VERSION 5.7 ;
BUSBITCHARS "[]" ;
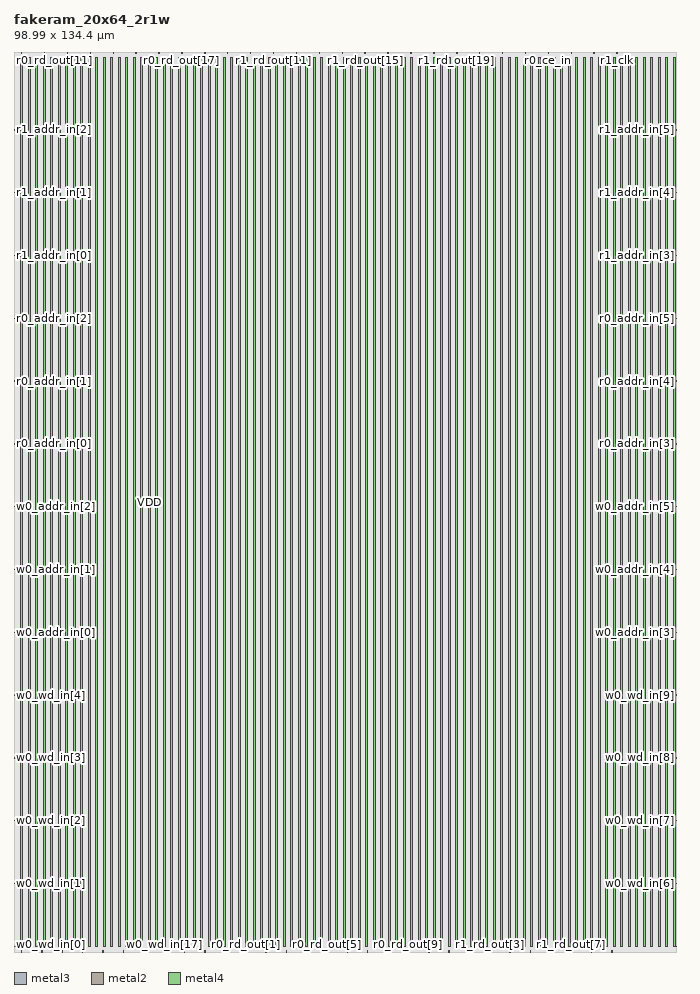
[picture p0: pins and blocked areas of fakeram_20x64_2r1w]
MACRO fakeram_20x64_2r1w
  FOREIGN fakeram_20x64_2r1w 0 0 ;
  SYMMETRY X Y R90 ;
  SIZE 98.990 BY 134.400 ;
  CLASS BLOCK ;
  PIN w0_wd_in[0]
    DIRECTION INPUT ;
    USE SIGNAL ;
    SHAPE ABUTMENT ;
    PORT
      LAYER metal3 ;
      RECT 0.000 0.805 0.210 0.875 ;
    END
  END w0_wd_in[0]
  PIN w0_wd_in[1]
    DIRECTION INPUT ;
    USE SIGNAL ;
    SHAPE ABUTMENT ;
    PORT
      LAYER metal3 ;
      RECT 0.000 10.185 0.210 10.255 ;
    END
  END w0_wd_in[1]
  PIN w0_wd_in[2]
    DIRECTION INPUT ;
    USE SIGNAL ;
    SHAPE ABUTMENT ;
    PORT
      LAYER metal3 ;
      RECT 0.000 19.565 0.210 19.635 ;
    END
  END w0_wd_in[2]
  PIN w0_wd_in[3]
    DIRECTION INPUT ;
    USE SIGNAL ;
    SHAPE ABUTMENT ;
    PORT
      LAYER metal3 ;
      RECT 0.000 28.945 0.210 29.015 ;
    END
  END w0_wd_in[3]
  PIN w0_wd_in[4]
    DIRECTION INPUT ;
    USE SIGNAL ;
    SHAPE ABUTMENT ;
    PORT
      LAYER metal3 ;
      RECT 0.000 38.325 0.210 38.395 ;
    END
  END w0_wd_in[4]
  PIN w0_wd_in[5]
    DIRECTION INPUT ;
    USE SIGNAL ;
    SHAPE ABUTMENT ;
    PORT
      LAYER metal3 ;
      RECT 98.780 0.805 98.990 0.875 ;
    END
  END w0_wd_in[5]
  PIN w0_wd_in[6]
    DIRECTION INPUT ;
    USE SIGNAL ;
    SHAPE ABUTMENT ;
    PORT
      LAYER metal3 ;
      RECT 98.780 10.185 98.990 10.255 ;
    END
  END w0_wd_in[6]
  PIN w0_wd_in[7]
    DIRECTION INPUT ;
    USE SIGNAL ;
    SHAPE ABUTMENT ;
    PORT
      LAYER metal3 ;
      RECT 98.780 19.565 98.990 19.635 ;
    END
  END w0_wd_in[7]
  PIN w0_wd_in[8]
    DIRECTION INPUT ;
    USE SIGNAL ;
    SHAPE ABUTMENT ;
    PORT
      LAYER metal3 ;
      RECT 98.780 28.945 98.990 29.015 ;
    END
  END w0_wd_in[8]
  PIN w0_wd_in[9]
    DIRECTION INPUT ;
    USE SIGNAL ;
    SHAPE ABUTMENT ;
    PORT
      LAYER metal3 ;
      RECT 98.780 38.325 98.990 38.395 ;
    END
  END w0_wd_in[9]
  PIN w0_wd_in[10]
    DIRECTION INPUT ;
    USE SIGNAL ;
    SHAPE ABUTMENT ;
    PORT
      LAYER metal2 ;
      RECT 1.105 0.000 1.175 0.210 ;
    END
  END w0_wd_in[10]
  PIN w0_wd_in[11]
    DIRECTION INPUT ;
    USE SIGNAL ;
    SHAPE ABUTMENT ;
    PORT
      LAYER metal2 ;
      RECT 4.145 0.000 4.215 0.210 ;
    END
  END w0_wd_in[11]
  PIN w0_wd_in[12]
    DIRECTION INPUT ;
    USE SIGNAL ;
    SHAPE ABUTMENT ;
    PORT
      LAYER metal2 ;
      RECT 7.185 0.000 7.255 0.210 ;
    END
  END w0_wd_in[12]
  PIN w0_wd_in[13]
    DIRECTION INPUT ;
    USE SIGNAL ;
    SHAPE ABUTMENT ;
    PORT
      LAYER metal2 ;
      RECT 10.225 0.000 10.295 0.210 ;
    END
  END w0_wd_in[13]
  PIN w0_wd_in[14]
    DIRECTION INPUT ;
    USE SIGNAL ;
    SHAPE ABUTMENT ;
    PORT
      LAYER metal2 ;
      RECT 13.265 0.000 13.335 0.210 ;
    END
  END w0_wd_in[14]
  PIN w0_wd_in[15]
    DIRECTION INPUT ;
    USE SIGNAL ;
    SHAPE ABUTMENT ;
    PORT
      LAYER metal2 ;
      RECT 16.305 0.000 16.375 0.210 ;
    END
  END w0_wd_in[15]
  PIN w0_wd_in[16]
    DIRECTION INPUT ;
    USE SIGNAL ;
    SHAPE ABUTMENT ;
    PORT
      LAYER metal2 ;
      RECT 19.345 0.000 19.415 0.210 ;
    END
  END w0_wd_in[16]
  PIN w0_wd_in[17]
    DIRECTION INPUT ;
    USE SIGNAL ;
    SHAPE ABUTMENT ;
    PORT
      LAYER metal2 ;
      RECT 22.385 0.000 22.455 0.210 ;
    END
  END w0_wd_in[17]
  PIN w0_wd_in[18]
    DIRECTION INPUT ;
    USE SIGNAL ;
    SHAPE ABUTMENT ;
    PORT
      LAYER metal2 ;
      RECT 25.425 0.000 25.495 0.210 ;
    END
  END w0_wd_in[18]
  PIN w0_wd_in[19]
    DIRECTION INPUT ;
    USE SIGNAL ;
    SHAPE ABUTMENT ;
    PORT
      LAYER metal2 ;
      RECT 28.465 0.000 28.535 0.210 ;
    END
  END w0_wd_in[19]
  PIN r0_rd_out[0]
    DIRECTION OUTPUT ;
    USE SIGNAL ;
    SHAPE ABUTMENT ;
    PORT
      LAYER metal2 ;
      RECT 31.505 0.000 31.575 0.210 ;
    END
  END r0_rd_out[0]
  PIN r0_rd_out[1]
    DIRECTION OUTPUT ;
    USE SIGNAL ;
    SHAPE ABUTMENT ;
    PORT
      LAYER metal2 ;
      RECT 34.545 0.000 34.615 0.210 ;
    END
  END r0_rd_out[1]
  PIN r0_rd_out[2]
    DIRECTION OUTPUT ;
    USE SIGNAL ;
    SHAPE ABUTMENT ;
    PORT
      LAYER metal2 ;
      RECT 37.585 0.000 37.655 0.210 ;
    END
  END r0_rd_out[2]
  PIN r0_rd_out[3]
    DIRECTION OUTPUT ;
    USE SIGNAL ;
    SHAPE ABUTMENT ;
    PORT
      LAYER metal2 ;
      RECT 40.625 0.000 40.695 0.210 ;
    END
  END r0_rd_out[3]
  PIN r0_rd_out[4]
    DIRECTION OUTPUT ;
    USE SIGNAL ;
    SHAPE ABUTMENT ;
    PORT
      LAYER metal2 ;
      RECT 43.665 0.000 43.735 0.210 ;
    END
  END r0_rd_out[4]
  PIN r0_rd_out[5]
    DIRECTION OUTPUT ;
    USE SIGNAL ;
    SHAPE ABUTMENT ;
    PORT
      LAYER metal2 ;
      RECT 46.705 0.000 46.775 0.210 ;
    END
  END r0_rd_out[5]
  PIN r0_rd_out[6]
    DIRECTION OUTPUT ;
    USE SIGNAL ;
    SHAPE ABUTMENT ;
    PORT
      LAYER metal2 ;
      RECT 49.745 0.000 49.815 0.210 ;
    END
  END r0_rd_out[6]
  PIN r0_rd_out[7]
    DIRECTION OUTPUT ;
    USE SIGNAL ;
    SHAPE ABUTMENT ;
    PORT
      LAYER metal2 ;
      RECT 52.785 0.000 52.855 0.210 ;
    END
  END r0_rd_out[7]
  PIN r0_rd_out[8]
    DIRECTION OUTPUT ;
    USE SIGNAL ;
    SHAPE ABUTMENT ;
    PORT
      LAYER metal2 ;
      RECT 55.825 0.000 55.895 0.210 ;
    END
  END r0_rd_out[8]
  PIN r0_rd_out[9]
    DIRECTION OUTPUT ;
    USE SIGNAL ;
    SHAPE ABUTMENT ;
    PORT
      LAYER metal2 ;
      RECT 58.865 0.000 58.935 0.210 ;
    END
  END r0_rd_out[9]
  PIN r0_rd_out[10]
    DIRECTION OUTPUT ;
    USE SIGNAL ;
    SHAPE ABUTMENT ;
    PORT
      LAYER metal2 ;
      RECT 1.105 134.190 1.175 134.400 ;
    END
  END r0_rd_out[10]
  PIN r0_rd_out[11]
    DIRECTION OUTPUT ;
    USE SIGNAL ;
    SHAPE ABUTMENT ;
    PORT
      LAYER metal2 ;
      RECT 4.525 134.190 4.595 134.400 ;
    END
  END r0_rd_out[11]
  PIN r0_rd_out[12]
    DIRECTION OUTPUT ;
    USE SIGNAL ;
    SHAPE ABUTMENT ;
    PORT
      LAYER metal2 ;
      RECT 7.945 134.190 8.015 134.400 ;
    END
  END r0_rd_out[12]
  PIN r0_rd_out[13]
    DIRECTION OUTPUT ;
    USE SIGNAL ;
    SHAPE ABUTMENT ;
    PORT
      LAYER metal2 ;
      RECT 11.365 134.190 11.435 134.400 ;
    END
  END r0_rd_out[13]
  PIN r0_rd_out[14]
    DIRECTION OUTPUT ;
    USE SIGNAL ;
    SHAPE ABUTMENT ;
    PORT
      LAYER metal2 ;
      RECT 14.785 134.190 14.855 134.400 ;
    END
  END r0_rd_out[14]
  PIN r0_rd_out[15]
    DIRECTION OUTPUT ;
    USE SIGNAL ;
    SHAPE ABUTMENT ;
    PORT
      LAYER metal2 ;
      RECT 18.205 134.190 18.275 134.400 ;
    END
  END r0_rd_out[15]
  PIN r0_rd_out[16]
    DIRECTION OUTPUT ;
    USE SIGNAL ;
    SHAPE ABUTMENT ;
    PORT
      LAYER metal2 ;
      RECT 21.625 134.190 21.695 134.400 ;
    END
  END r0_rd_out[16]
  PIN r0_rd_out[17]
    DIRECTION OUTPUT ;
    USE SIGNAL ;
    SHAPE ABUTMENT ;
    PORT
      LAYER metal2 ;
      RECT 25.045 134.190 25.115 134.400 ;
    END
  END r0_rd_out[17]
  PIN r0_rd_out[18]
    DIRECTION OUTPUT ;
    USE SIGNAL ;
    SHAPE ABUTMENT ;
    PORT
      LAYER metal2 ;
      RECT 28.465 134.190 28.535 134.400 ;
    END
  END r0_rd_out[18]
  PIN r0_rd_out[19]
    DIRECTION OUTPUT ;
    USE SIGNAL ;
    SHAPE ABUTMENT ;
    PORT
      LAYER metal2 ;
      RECT 31.885 134.190 31.955 134.400 ;
    END
  END r0_rd_out[19]
  PIN r1_rd_out[0]
    DIRECTION OUTPUT ;
    USE SIGNAL ;
    SHAPE ABUTMENT ;
    PORT
      LAYER metal2 ;
      RECT 61.905 0.000 61.975 0.210 ;
    END
  END r1_rd_out[0]
  PIN r1_rd_out[1]
    DIRECTION OUTPUT ;
    USE SIGNAL ;
    SHAPE ABUTMENT ;
    PORT
      LAYER metal2 ;
      RECT 64.945 0.000 65.015 0.210 ;
    END
  END r1_rd_out[1]
  PIN r1_rd_out[2]
    DIRECTION OUTPUT ;
    USE SIGNAL ;
    SHAPE ABUTMENT ;
    PORT
      LAYER metal2 ;
      RECT 67.985 0.000 68.055 0.210 ;
    END
  END r1_rd_out[2]
  PIN r1_rd_out[3]
    DIRECTION OUTPUT ;
    USE SIGNAL ;
    SHAPE ABUTMENT ;
    PORT
      LAYER metal2 ;
      RECT 71.025 0.000 71.095 0.210 ;
    END
  END r1_rd_out[3]
  PIN r1_rd_out[4]
    DIRECTION OUTPUT ;
    USE SIGNAL ;
    SHAPE ABUTMENT ;
    PORT
      LAYER metal2 ;
      RECT 74.065 0.000 74.135 0.210 ;
    END
  END r1_rd_out[4]
  PIN r1_rd_out[5]
    DIRECTION OUTPUT ;
    USE SIGNAL ;
    SHAPE ABUTMENT ;
    PORT
      LAYER metal2 ;
      RECT 77.105 0.000 77.175 0.210 ;
    END
  END r1_rd_out[5]
  PIN r1_rd_out[6]
    DIRECTION OUTPUT ;
    USE SIGNAL ;
    SHAPE ABUTMENT ;
    PORT
      LAYER metal2 ;
      RECT 80.145 0.000 80.215 0.210 ;
    END
  END r1_rd_out[6]
  PIN r1_rd_out[7]
    DIRECTION OUTPUT ;
    USE SIGNAL ;
    SHAPE ABUTMENT ;
    PORT
      LAYER metal2 ;
      RECT 83.185 0.000 83.255 0.210 ;
    END
  END r1_rd_out[7]
  PIN r1_rd_out[8]
    DIRECTION OUTPUT ;
    USE SIGNAL ;
    SHAPE ABUTMENT ;
    PORT
      LAYER metal2 ;
      RECT 86.225 0.000 86.295 0.210 ;
    END
  END r1_rd_out[8]
  PIN r1_rd_out[9]
    DIRECTION OUTPUT ;
    USE SIGNAL ;
    SHAPE ABUTMENT ;
    PORT
      LAYER metal2 ;
      RECT 89.265 0.000 89.335 0.210 ;
    END
  END r1_rd_out[9]
  PIN r1_rd_out[10]
    DIRECTION OUTPUT ;
    USE SIGNAL ;
    SHAPE ABUTMENT ;
    PORT
      LAYER metal2 ;
      RECT 35.305 134.190 35.375 134.400 ;
    END
  END r1_rd_out[10]
  PIN r1_rd_out[11]
    DIRECTION OUTPUT ;
    USE SIGNAL ;
    SHAPE ABUTMENT ;
    PORT
      LAYER metal2 ;
      RECT 38.725 134.190 38.795 134.400 ;
    END
  END r1_rd_out[11]
  PIN r1_rd_out[12]
    DIRECTION OUTPUT ;
    USE SIGNAL ;
    SHAPE ABUTMENT ;
    PORT
      LAYER metal2 ;
      RECT 42.145 134.190 42.215 134.400 ;
    END
  END r1_rd_out[12]
  PIN r1_rd_out[13]
    DIRECTION OUTPUT ;
    USE SIGNAL ;
    SHAPE ABUTMENT ;
    PORT
      LAYER metal2 ;
      RECT 45.565 134.190 45.635 134.400 ;
    END
  END r1_rd_out[13]
  PIN r1_rd_out[14]
    DIRECTION OUTPUT ;
    USE SIGNAL ;
    SHAPE ABUTMENT ;
    PORT
      LAYER metal2 ;
      RECT 48.985 134.190 49.055 134.400 ;
    END
  END r1_rd_out[14]
  PIN r1_rd_out[15]
    DIRECTION OUTPUT ;
    USE SIGNAL ;
    SHAPE ABUTMENT ;
    PORT
      LAYER metal2 ;
      RECT 52.405 134.190 52.475 134.400 ;
    END
  END r1_rd_out[15]
  PIN r1_rd_out[16]
    DIRECTION OUTPUT ;
    USE SIGNAL ;
    SHAPE ABUTMENT ;
    PORT
      LAYER metal2 ;
      RECT 55.825 134.190 55.895 134.400 ;
    END
  END r1_rd_out[16]
  PIN r1_rd_out[17]
    DIRECTION OUTPUT ;
    USE SIGNAL ;
    SHAPE ABUTMENT ;
    PORT
      LAYER metal2 ;
      RECT 59.245 134.190 59.315 134.400 ;
    END
  END r1_rd_out[17]
  PIN r1_rd_out[18]
    DIRECTION OUTPUT ;
    USE SIGNAL ;
    SHAPE ABUTMENT ;
    PORT
      LAYER metal2 ;
      RECT 62.665 134.190 62.735 134.400 ;
    END
  END r1_rd_out[18]
  PIN r1_rd_out[19]
    DIRECTION OUTPUT ;
    USE SIGNAL ;
    SHAPE ABUTMENT ;
    PORT
      LAYER metal2 ;
      RECT 66.085 134.190 66.155 134.400 ;
    END
  END r1_rd_out[19]
  PIN w0_addr_in[0]
    DIRECTION INPUT ;
    USE SIGNAL ;
    SHAPE ABUTMENT ;
    PORT
      LAYER metal3 ;
      RECT 0.000 47.705 0.210 47.775 ;
    END
  END w0_addr_in[0]
  PIN w0_addr_in[1]
    DIRECTION INPUT ;
    USE SIGNAL ;
    SHAPE ABUTMENT ;
    PORT
      LAYER metal3 ;
      RECT 0.000 57.085 0.210 57.155 ;
    END
  END w0_addr_in[1]
  PIN w0_addr_in[2]
    DIRECTION INPUT ;
    USE SIGNAL ;
    SHAPE ABUTMENT ;
    PORT
      LAYER metal3 ;
      RECT 0.000 66.465 0.210 66.535 ;
    END
  END w0_addr_in[2]
  PIN w0_addr_in[3]
    DIRECTION INPUT ;
    USE SIGNAL ;
    SHAPE ABUTMENT ;
    PORT
      LAYER metal3 ;
      RECT 98.780 47.705 98.990 47.775 ;
    END
  END w0_addr_in[3]
  PIN w0_addr_in[4]
    DIRECTION INPUT ;
    USE SIGNAL ;
    SHAPE ABUTMENT ;
    PORT
      LAYER metal3 ;
      RECT 98.780 57.085 98.990 57.155 ;
    END
  END w0_addr_in[4]
  PIN w0_addr_in[5]
    DIRECTION INPUT ;
    USE SIGNAL ;
    SHAPE ABUTMENT ;
    PORT
      LAYER metal3 ;
      RECT 98.780 66.465 98.990 66.535 ;
    END
  END w0_addr_in[5]
  PIN r0_addr_in[0]
    DIRECTION INPUT ;
    USE SIGNAL ;
    SHAPE ABUTMENT ;
    PORT
      LAYER metal3 ;
      RECT 0.000 75.845 0.210 75.915 ;
    END
  END r0_addr_in[0]
  PIN r0_addr_in[1]
    DIRECTION INPUT ;
    USE SIGNAL ;
    SHAPE ABUTMENT ;
    PORT
      LAYER metal3 ;
      RECT 0.000 85.225 0.210 85.295 ;
    END
  END r0_addr_in[1]
  PIN r0_addr_in[2]
    DIRECTION INPUT ;
    USE SIGNAL ;
    SHAPE ABUTMENT ;
    PORT
      LAYER metal3 ;
      RECT 0.000 94.605 0.210 94.675 ;
    END
  END r0_addr_in[2]
  PIN r0_addr_in[3]
    DIRECTION INPUT ;
    USE SIGNAL ;
    SHAPE ABUTMENT ;
    PORT
      LAYER metal3 ;
      RECT 98.780 75.845 98.990 75.915 ;
    END
  END r0_addr_in[3]
  PIN r0_addr_in[4]
    DIRECTION INPUT ;
    USE SIGNAL ;
    SHAPE ABUTMENT ;
    PORT
      LAYER metal3 ;
      RECT 98.780 85.225 98.990 85.295 ;
    END
  END r0_addr_in[4]
  PIN r0_addr_in[5]
    DIRECTION INPUT ;
    USE SIGNAL ;
    SHAPE ABUTMENT ;
    PORT
      LAYER metal3 ;
      RECT 98.780 94.605 98.990 94.675 ;
    END
  END r0_addr_in[5]
  PIN r1_addr_in[0]
    DIRECTION INPUT ;
    USE SIGNAL ;
    SHAPE ABUTMENT ;
    PORT
      LAYER metal3 ;
      RECT 0.000 103.985 0.210 104.055 ;
    END
  END r1_addr_in[0]
  PIN r1_addr_in[1]
    DIRECTION INPUT ;
    USE SIGNAL ;
    SHAPE ABUTMENT ;
    PORT
      LAYER metal3 ;
      RECT 0.000 113.365 0.210 113.435 ;
    END
  END r1_addr_in[1]
  PIN r1_addr_in[2]
    DIRECTION INPUT ;
    USE SIGNAL ;
    SHAPE ABUTMENT ;
    PORT
      LAYER metal3 ;
      RECT 0.000 122.745 0.210 122.815 ;
    END
  END r1_addr_in[2]
  PIN r1_addr_in[3]
    DIRECTION INPUT ;
    USE SIGNAL ;
    SHAPE ABUTMENT ;
    PORT
      LAYER metal3 ;
      RECT 98.780 103.985 98.990 104.055 ;
    END
  END r1_addr_in[3]
  PIN r1_addr_in[4]
    DIRECTION INPUT ;
    USE SIGNAL ;
    SHAPE ABUTMENT ;
    PORT
      LAYER metal3 ;
      RECT 98.780 113.365 98.990 113.435 ;
    END
  END r1_addr_in[4]
  PIN r1_addr_in[5]
    DIRECTION INPUT ;
    USE SIGNAL ;
    SHAPE ABUTMENT ;
    PORT
      LAYER metal3 ;
      RECT 98.780 122.745 98.990 122.815 ;
    END
  END r1_addr_in[5]
  PIN w0_we_in
    DIRECTION INPUT ;
    USE SIGNAL ;
    SHAPE ABUTMENT ;
    PORT
      LAYER metal2 ;
      RECT 69.505 134.190 69.575 134.400 ;
    END
  END w0_we_in
  PIN w0_ce_in
    DIRECTION INPUT ;
    USE SIGNAL ;
    SHAPE ABUTMENT ;
    PORT
      LAYER metal2 ;
      RECT 72.925 134.190 72.995 134.400 ;
    END
  END w0_ce_in
  PIN w0_clk
    DIRECTION INPUT ;
    USE SIGNAL ;
    SHAPE ABUTMENT ;
    PORT
      LAYER metal2 ;
      RECT 76.345 134.190 76.415 134.400 ;
    END
  END w0_clk
  PIN r0_ce_in
    DIRECTION INPUT ;
    USE SIGNAL ;
    SHAPE ABUTMENT ;
    PORT
      LAYER metal2 ;
      RECT 79.765 134.190 79.835 134.400 ;
    END
  END r0_ce_in
  PIN r0_clk
    DIRECTION INPUT ;
    USE SIGNAL ;
    SHAPE ABUTMENT ;
    PORT
      LAYER metal2 ;
      RECT 83.185 134.190 83.255 134.400 ;
    END
  END r0_clk
  PIN r1_ce_in
    DIRECTION INPUT ;
    USE SIGNAL ;
    SHAPE ABUTMENT ;
    PORT
      LAYER metal2 ;
      RECT 86.605 134.190 86.675 134.400 ;
    END
  END r1_ce_in
  PIN r1_clk
    DIRECTION INPUT ;
    USE SIGNAL ;
    SHAPE ABUTMENT ;
    PORT
      LAYER metal2 ;
      RECT 90.025 134.190 90.095 134.400 ;
    END
  END r1_clk
  PIN VSS
    DIRECTION INOUT ;
    USE GROUND ;
    PORT
      LAYER metal4 ;
      RECT 1.000 0.840 1.280 133.560 ;
      RECT 3.240 0.840 3.520 133.560 ;
      RECT 5.480 0.840 5.760 133.560 ;
      RECT 7.720 0.840 8.000 133.560 ;
      RECT 9.960 0.840 10.240 133.560 ;
      RECT 12.200 0.840 12.480 133.560 ;
      RECT 14.440 0.840 14.720 133.560 ;
      RECT 16.680 0.840 16.960 133.560 ;
      RECT 18.920 0.840 19.200 133.560 ;
      RECT 21.160 0.840 21.440 133.560 ;
      RECT 23.400 0.840 23.680 133.560 ;
      RECT 25.640 0.840 25.920 133.560 ;
      RECT 27.880 0.840 28.160 133.560 ;
      RECT 30.120 0.840 30.400 133.560 ;
      RECT 32.360 0.840 32.640 133.560 ;
      RECT 34.600 0.840 34.880 133.560 ;
      RECT 36.840 0.840 37.120 133.560 ;
      RECT 39.080 0.840 39.360 133.560 ;
      RECT 41.320 0.840 41.600 133.560 ;
      RECT 43.560 0.840 43.840 133.560 ;
      RECT 45.800 0.840 46.080 133.560 ;
      RECT 48.040 0.840 48.320 133.560 ;
      RECT 50.280 0.840 50.560 133.560 ;
      RECT 52.520 0.840 52.800 133.560 ;
      RECT 54.760 0.840 55.040 133.560 ;
      RECT 57.000 0.840 57.280 133.560 ;
      RECT 59.240 0.840 59.520 133.560 ;
      RECT 61.480 0.840 61.760 133.560 ;
      RECT 63.720 0.840 64.000 133.560 ;
      RECT 65.960 0.840 66.240 133.560 ;
      RECT 68.200 0.840 68.480 133.560 ;
      RECT 70.440 0.840 70.720 133.560 ;
      RECT 72.680 0.840 72.960 133.560 ;
      RECT 74.920 0.840 75.200 133.560 ;
      RECT 77.160 0.840 77.440 133.560 ;
      RECT 79.400 0.840 79.680 133.560 ;
      RECT 81.640 0.840 81.920 133.560 ;
      RECT 83.880 0.840 84.160 133.560 ;
      RECT 86.120 0.840 86.400 133.560 ;
      RECT 88.360 0.840 88.640 133.560 ;
      RECT 90.600 0.840 90.880 133.560 ;
      RECT 92.840 0.840 93.120 133.560 ;
      RECT 95.080 0.840 95.360 133.560 ;
      RECT 97.320 0.840 97.600 133.560 ;
    END
  END VSS
  PIN VDD
    DIRECTION INOUT ;
    USE POWER ;
    PORT
      LAYER metal4 ;
      RECT 2.120 0.840 2.400 133.560 ;
      RECT 4.360 0.840 4.640 133.560 ;
      RECT 6.600 0.840 6.880 133.560 ;
      RECT 8.840 0.840 9.120 133.560 ;
      RECT 11.080 0.840 11.360 133.560 ;
      RECT 13.320 0.840 13.600 133.560 ;
      RECT 15.560 0.840 15.840 133.560 ;
      RECT 17.800 0.840 18.080 133.560 ;
      RECT 20.040 0.840 20.320 133.560 ;
      RECT 22.280 0.840 22.560 133.560 ;
      RECT 24.520 0.840 24.800 133.560 ;
      RECT 26.760 0.840 27.040 133.560 ;
      RECT 29.000 0.840 29.280 133.560 ;
      RECT 31.240 0.840 31.520 133.560 ;
      RECT 33.480 0.840 33.760 133.560 ;
      RECT 35.720 0.840 36.000 133.560 ;
      RECT 37.960 0.840 38.240 133.560 ;
      RECT 40.200 0.840 40.480 133.560 ;
      RECT 42.440 0.840 42.720 133.560 ;
      RECT 44.680 0.840 44.960 133.560 ;
      RECT 46.920 0.840 47.200 133.560 ;
      RECT 49.160 0.840 49.440 133.560 ;
      RECT 51.400 0.840 51.680 133.560 ;
      RECT 53.640 0.840 53.920 133.560 ;
      RECT 55.880 0.840 56.160 133.560 ;
      RECT 58.120 0.840 58.400 133.560 ;
      RECT 60.360 0.840 60.640 133.560 ;
      RECT 62.600 0.840 62.880 133.560 ;
      RECT 64.840 0.840 65.120 133.560 ;
      RECT 67.080 0.840 67.360 133.560 ;
      RECT 69.320 0.840 69.600 133.560 ;
      RECT 71.560 0.840 71.840 133.560 ;
      RECT 73.800 0.840 74.080 133.560 ;
      RECT 76.040 0.840 76.320 133.560 ;
      RECT 78.280 0.840 78.560 133.560 ;
      RECT 80.520 0.840 80.800 133.560 ;
      RECT 82.760 0.840 83.040 133.560 ;
      RECT 85.000 0.840 85.280 133.560 ;
      RECT 87.240 0.840 87.520 133.560 ;
      RECT 89.480 0.840 89.760 133.560 ;
      RECT 91.720 0.840 92.000 133.560 ;
      RECT 93.960 0.840 94.240 133.560 ;
      RECT 96.200 0.840 96.480 133.560 ;
      RECT 98.440 0.840 98.720 133.560 ;
    END
  END VDD
  OBS
    LAYER metal1 ;
    RECT 0 0 98.990 134.400 ;
    LAYER metal2 ;
    RECT 0 0 98.990 134.400 ;
    LAYER metal3 ;
    RECT 0 0 98.990 134.400 ;
    LAYER metal4 ;
    RECT 0 0 98.990 134.400 ;
    LAYER OVERLAP ;
    RECT 0 0 98.990 134.400 ;
  END
END fakeram_20x64_2r1w

END LIBRARY
